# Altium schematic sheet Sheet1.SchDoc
size A4; SheetNumber: 1; SheetTotal: 1

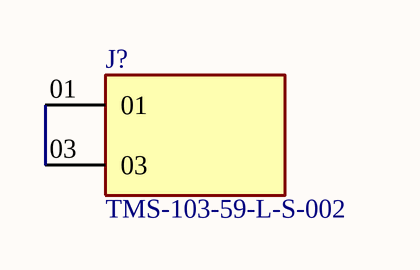
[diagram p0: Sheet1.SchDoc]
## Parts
J?  TMS-103-59-L-S-002  [SAMTEC_TMS-103-59-L-S-002]

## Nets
NetJ?_01: J?.01 J?.03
